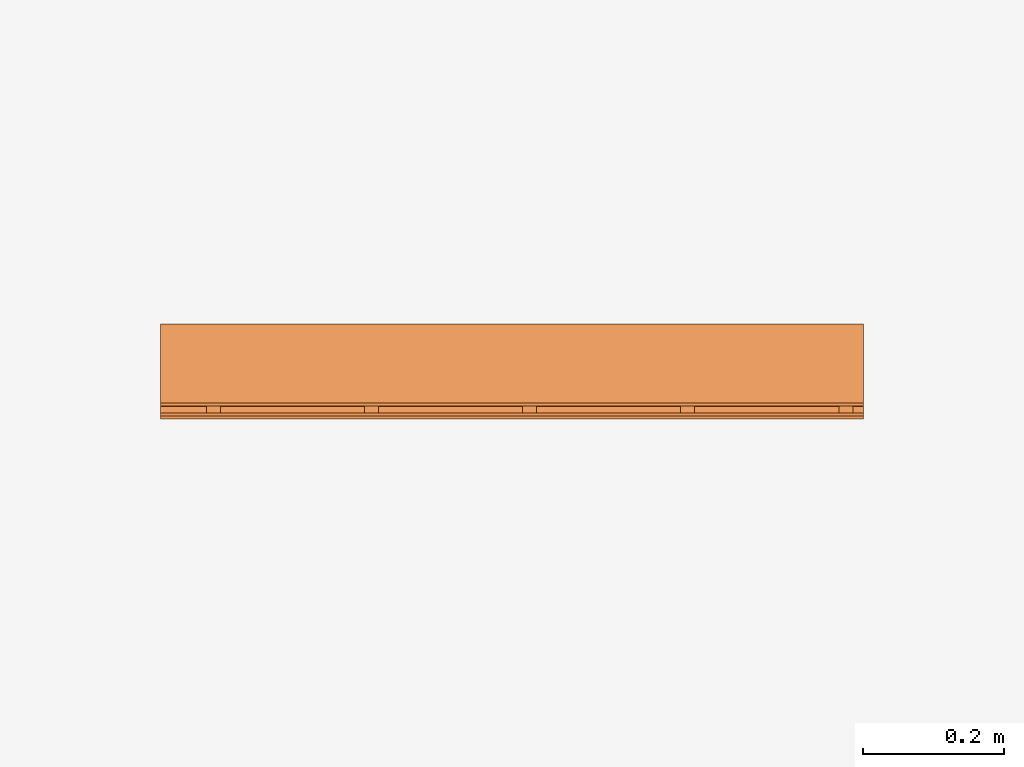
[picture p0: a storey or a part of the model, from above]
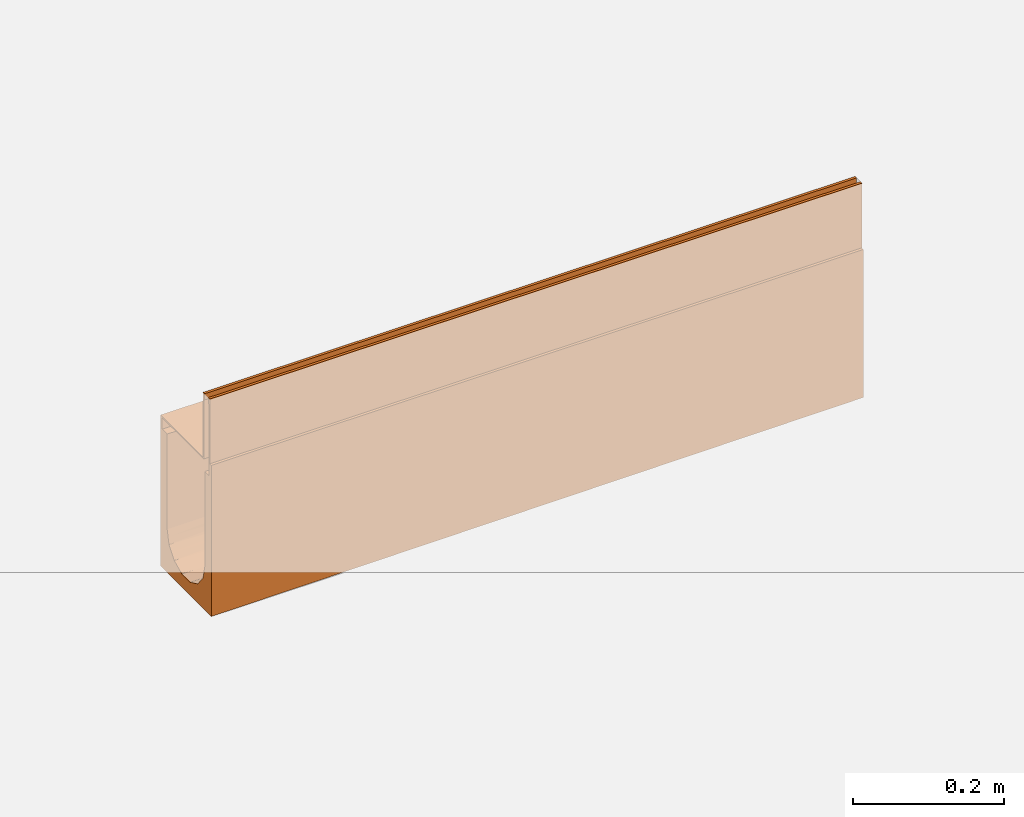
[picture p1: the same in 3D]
Properties of the parts of a building model (IFC2X3)

# File
Description: ViewDefinition [CoordinationView]
File name: 23019 - No 19 Sloping Channel - 1000mm LG - Invert Depth 220-225mm.ifc
Time: 2013-10-31T17:29:34
Written by: Autodesk Revit 2013
Made in: 20120221_2030(x64)

# IfcProject, Project Number
LongName: Project Name; Phase: Project Status

# IfcSite, Default
RefLatitude: 42, 21, 30, 344238; RefLongitude: -71, -3, -35, -194702; RefElevation: 0 mm

# IfcBuilding
Pset_BuildingCommon - NumberOfStoreys: 1
Other - Project Name: Project Name; Project Address: ## Street City, State Zip; Client Name: Owner; Project Number: Project Number; Project Status: Project Status; Project Issue Date: Issue Date

# IfcBuildingStorey, Level 1
LongName: Level 1; Elevation: 0 mm
Constraints - Elevation Base: 0; Elevation: 0 mm
Graphics - Line Pattern: Center; Color: 0; Symbol at End 2 Default: yes; Line Weight: 1; Symbol at End 1 Default: no; Symbol: M_Level Head - Circle: M_Level Head - Circle
Dimensions - Computation Height: 0 mm
Identity Data - Building Story: yes; Structural: no; Name: Level 1

# IfcBuildingElementProxy: 23019 - No 19 Sloping Channel - 1000mm LG - Invert Depth 220/225mm, Civil-Drainage-Channel-ACO-MultiDrain-M100D-Brickslot-Channel-System:23019 - No 19 Sloping Channel - 1000mm LG - Invert Depth 220/225mm:23019 - No 19 Sloping Channel - 1000mm LG - Invert Depth 220/225mm:196059
In: Level 1
Material: Steel, Galvanized, Vienite® Synthetic Resin Concrete
Dimensions - Volume: 11826148 mm3; Brickslot Access Unit Void Depth: -6500 mm; Brickslot Void Length: 1000 mm; EndCap Position: 1000 mm; FloorCut_Length: -1000 mm; Brickslot Access Unit Void Bottom Depth: -6605 mm; Length: 1000 mm; Brickslot Void Depth: 0 mm; Custom_Void_length: 0 mm; SlopingEndOverallDepth: 245 mm; ShallowOverallDepth: 75 mm; FloorCut_Depth: 245 mm; EndCap_Height: 245 mm; Floor Cut Gap: 105 mm; InvDepth: 80 mm; GratingLength: -1000 mm; Brickslot Access Unit Floor Cut Length: 500 mm; SlopingOverallDepth: 240 mm; SlopingEndInvertDepth: 175 mm; FloorCut_Width: 135 mm; ShallowInvDepth: 55 mm; SlopingInvertDepth: 170 mm; Length Drain: -1000 mm; Access_Custom_Void_Length: 0 mm; Depth: 150 mm
Constraints - Moves With Nearby Elements: no; Level: Level: Level 1
Phasing - Phase Created: New Construction
Construction - 23466_Load Class D400_Brickslot Grating_Galvanized Steel_500mm Long: no; 23462_Load Class C250_Brickslot Access Unit_Galvanised Steel_500mm Long: no; 23465_Load Class D400_Brickslot Grating_Galvanized Steel_1000mm Long: yes; 23404_Universal Endcap (Male End): no; 23404_Universal Endcap (Female End): no; 23461_Load Class C250_Brickslot Grating_Galvanized Steel_500mm Long: no; 23467_Load Class D400_Brickslot Access Unit_Galvanised Steel_500mm Long: no; 23460_Load Class C250_Brickslot Grating_Galvanized Steel_1000mm Long: no; Sloping Channel: yes; Shallow Depth Channel: no; Constant Depth Channel: no; 23410_Sump Unit: no; Shallow Depth Channel with seal: no; Constant Depth Junction Channel: no
Pset_BuildingElementProxyCommon - Reference: 23019 - No 19 Sloping Channel - 1000mm LG - Invert Depth 220/225mm
Identity Data - Watermarked With: BIM Manager Premium Suite; Fax: +44 (0)1462 815895; Model Description: Channel drainage system; Product Code: 23019; Maintenance guidelines: http://www.aco.co.uk/download.php?id=173; Assembly Code: D2040; Type Comments: ACO MultiDrain M100D No 19 Sloping Channel 1000mm Long; URL: www.aco.co.uk; Product brochure: http://www.aco.co.uk/download.php?id=173; Assembly Description: Rain Water Drainage; Price: POA - contact ACO; Watermark 1: This file is the property of ACO Technologies PLC; Product Page URL: http://www.aco.co.uk/product_detail.php?id=58; Model: ACO MultiDrain MD Brickslot- M100D; Manufacturer: ACO Technologies plc - ACO Water Management Division; e-mail Technical: technical@aco.co.uk; Cost: 0; OmniClass Title: Rainwater Removal; Telephone: +44 (0)1462 816666; Watermark 2: This file is water marked and users are prohibited to reproduce, adapt, distribute this information; Installation guidelines: http://www.aco.co.uk/download.php?id=173; OmniClass Number: 23.70.50.24; Address: ACO Business Park, Hitchin Road, Shefford, Bedfordshire, United Kingdom SG17 5TE; e-mail Sales: customersupport@aco.co.uk
Data - Invert Depth: 220mm/225mm; Product Standard: BS EN 1433:2002, CE marked; Channel C.S.A: N/A; Product Dimensions: 1000mm x 135mm x 240mm/245mm (LxWxH); Load Class: A 15 - D 400; Pre-formed Outlet Ø: N/A; Hydraulic Performance: http://www.aco.co.uk/download.php?id=173; Product Weight: 18.9 Kg; ACO Hydraulic Design Software: http://www.acodesign.co.uk; Installation - Concrete Grade: Refer to brochure; Concrete Surround Volume - Load Class B 125 - C 250 - Concrete Pavement: N/A; Concrete Surround Volume - Load Class D 400 - Concrete Pavement: N/A; Concrete Surround Volume - Load Class A 15 - Concrete Pavement: N/A
Model Properties - Brickslot Grating Product code 23466: Load Class D400 - Brickslot Galvanised Steel - 500mm long x 105mm high - 10mm Slot - Intake area - 10000mm²/m - 3.3 Kg; End Cap Product code 23404: No 306 Universal End Cap - 135mm wide x 300mm long - Spigot Ø110mm x 50mm long - Silver - Polypropylene - 0.16kg; Brickslot Access Unit Product code 23467: Load Class D400 - Brickslot Access Unit Galvanised Steel - 500mm long x 105mm high - 10mm Slot - Intake area - 10000mm²/m - 6.4 Kg; Brickslot Grating Product code 23465: Load Class D400 - Brickslot Galvanised Steel - 1000mm long x 105mm high - 10mm Slot - Intake area - 10000mm²/m - 6.6 Kg; Brickslot Grating Product code 23461: Load Class C250 - Brickslot Galvanised Steel - 500mm long x 105mm high - 10mm Slot - Intake area - 10000mm²/m -3.3 Kg; Brickslot Grating Product code 23460: Load Class C250 - Brickslot Galvanised Steel - 1000mm long x 105mm high - 10mm Slot - Intake area - 10000mm²/m - 6.6 Kg; Brickslot Access Unit Product code 23462: Load Class C250 - Brickslot Access Unit Galvanised Steel - 500mm long x 105mm high - 10mm Slot - Intake area - 10000mm²/m - 6.4 Kg
General - SerialNumber: 0; TagNumber: 0
Materials and Finishes - Channel Colour: Brown; Edge Rail Finish: Pre-galvanised; Edge Rail Colour: Silver; Edge Rail Material: Steel; Channel Material: Vienite® Synthetic Resin Concrete
Other - Watermarked By: www.aco.co.uk; Created By: www.aco.co.uk; Revision: 1
Green Building Properties - Edge Rail Recyclable: Fully recyclable; Edge Rail Recycled Material Content: Between 40% - 90%; Channel Recycled Material Content: 20% minimum; Channel Recyclable: Fully recyclable

# IfcOpeningElement: Recess (2)
In: Level 1
Constraints - Related to Mass: no; Room Bounding: yes; Height Offset From Level: 0 mm; Level: Level: Level 1
Structural - Structural: no; Enable Analytical Model: no
Dimensions - Volume: 24965035000 mm3; Perimeter: 20000 mm; Thickness: 1000 mm; Area: 25000000 mm2
Phasing - Phase Created: New Construction
Graphics - Coarse Scale Fill Color: 0
Construction - Default Thickness: 1000 mm; Function: 0
Materials and Finishes - Structural Material: Earth
Analytical Properties - Heat Transfer Coefficient (U): 0.837; Thermal Resistance (R): 1.19474; Thermal mass: 1359800; Absorptance: 0.1; Roughness: 1

# IfcSlab: Floor:Generic Floor - 1000mm, Floor:Generic Floor - 1000mm:193825
In: Level 1
PredefinedType: FLOOR; Material: Earth 1000 mm
Constraints - Related to Mass: no; Room Bounding: yes; Height Offset From Level: 0 mm; Level: Level: Level 1
Structural - Structural: no; Enable Analytical Model: no
Dimensions - Volume: 24965035000 mm3; Perimeter: 20000 mm; Thickness: 1000 mm; Area: 25000000 mm2
Phasing - Phase Created: New Construction
Pset_SlabCommon - Reference: Generic Floor - 1000mm; IsExternal: no; LoadBearing: yes
Graphics - Coarse Scale Fill Color: 0
Construction - Default Thickness: 1000 mm; Function: 0
Materials and Finishes - Structural Material: Earth
Analytical Properties - Heat Transfer Coefficient (U): 0.837; Thermal Resistance (R): 1.19474; Thermal mass: 1359800; Absorptance: 0.1; Roughness: 1
